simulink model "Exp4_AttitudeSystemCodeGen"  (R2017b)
settings: Solver=FixedStepDiscrete  StartTime=0.0  StopTime=inf  RelTol=1e-3
PreLoadFcn:
  | filepath  = fileparts(get_param(bdroot, 'FileName'))
  | cd(filepath);
InitFcn:
  | if exist('Init_control.m','file')
  |      Init_control;
  | end
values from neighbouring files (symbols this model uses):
  KiPitchAttitude = 0.0552303199591522 / kFactor    (= 0.0460252666326)    [Init_control.m]
  KiPitchRate = 0.460338699849681 / kFactor    (= 0.383615583208)    [Init_control.m]
  KiRollAttitude = 0.0552303199591522 / kFactor    (= 0.0460252666326)    [Init_control.m]
  KiRollRate = 0.460338699849681 / kFactor    (= 0.383615583208)    [Init_control.m]
  KiYawRate = 0.460338699849681 / kFactor * 2    (= 0.767231166416)    [Init_control.m]
  KpPitchAttitude = 0.630138625117681 / kFactor    (= 0.525115520931)    [Init_control.m]
  KpPitchRate = 1.31533836563383 / kFactor    (= 1.09611530469)    [Init_control.m]
  KpRollAttitude = 0.630138625117681 / kFactor    (= 0.525115520931)    [Init_control.m]
  KpRollRate = 1.31533836563383 / kFactor    (= 1.09611530469)    [Init_control.m]
  KpYawRate = 1.31533836563383 / kFactor * 2    (= 2.19223060939)    [Init_control.m]
undefined symbols (not defined in the file or in its folder): current_a, current_filtered_a, remaining, RGBLED_COLOR_ENUM, RGBLED_MODE_ENUM, voltage_filtered_v, voltage_v
libraries: simulink x6, pixhawk_slib_sensors_actuators x3, pixhawk_slib_uORB_RW x2

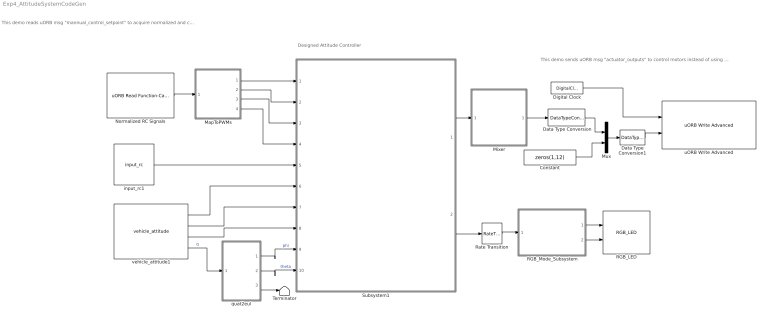
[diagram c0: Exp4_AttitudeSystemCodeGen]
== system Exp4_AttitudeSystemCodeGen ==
  note: Designed Attitude Controller
  note: This demo reads uORB msg "mannual_control_setpoint" to acquire normalized and calibrated RC signals (-1~1 for pitch, roll, yaw control, and 0~1 for throttle control) and then map them to 1000~2000's PWMs values. Compared with using the "input_rc" module to read RC PWM values directlly, this is more reliable and convinenient because you don't need to worry about calibration of RCs.
  note: This demo sends uORB msg "actuator_outputs" to control motors instead of using the "PWM_output" module, because this demo is for hardware-in-the-loop simulation, we need to send control signals to CopterSim instead of acutal motors.
  Constant : Constant  Value=zeros(1,12)
  Data Type Conversion : DataTypeConversion  OutDataTypeStr=double
  Data Type Conversion1 : DataTypeConversion  OutDataTypeStr=single
  Digital Clock : DigitalClock  SampleTime=-1
  MapToPWMs : Subsystem
  Mixer : Subsystem
  Mux : Mux  Inputs=2
  Normalized RC Signals : pixhawk_slib_uORB_RW/uORB Read Function-Call Trigger  uORB_Topic_str='manual_control_setpoint'  BusObjVar=Bus: manual_control_setpoint_SL  uORB_Interval=1  AsyncOutput=off  Fcn_call_select=Generate Function Call Signal  TaskName='Task1'  Poll_timeout=100  Ts=-1
  RGB_LED : pixhawk_slib_sensors_actuators/RGB_LED
  RGB_Mode_Subsystem : Subsystem
  Rate Transition : RateTransition  OutPortSampleTime=1
  Subsystem1 : Subsystem
  Terminator : Terminator
  input_rc1 : pixhawk_slib_sensors_actuators/input_rc  Description=|  sampletime=1/250  channel1=off  channel2=off  channel3=off  channel4=off  channel5=on  channel6=off  channel7=off  channel8=off  channel9=off  channel10=off  channel11=off  channel12=off  channel13=off  channel14=off  channel15=off  channel16=off  channel17=off  channel18=off  ch_count=off  rssi=off  rc_failsafe=off  rc_lost=off  rc_inputsource=off
      | RC Input Block
      | 
      | This block provides user input control to the model.
      | It uses the input_rc uORB topic.
      | 
      | The user has the ability to choose which channels are available as outputs from this block and also some optional outputs. These include 
      | Channels 1 through 18
      | double data type indicating the PWM value from the controller 
      | measured pulse widths for each of the supported channels 
      | Channel Count 
      | u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
  quat2eul : MATLAB Function  TreatAsAtomicUnit=on
  uORB Write Advanced : pixhawk_slib_uORB_RW/uORB Write Advanced  Ts=0  uORB_AdvtQueue=on  uORB_FieldEnabledArr="0  0  0  1  0  0  0  0  0  0  0"  uORB_Topic_str=0  uORB_Struct_DT="[1  1  1  1  1]"  BlockInputCount=5  uORB_StructParams="[\"voltage_v\",\"voltage_filtered_v\",\"current_a\",\"current_filtered_a\",\"remaining\"]"  uORB_PortSizes="[1  1  1  1]"  MsgSizeOf=0  MW_update=true
  vehicle_attitude1 : pixhawk_slib_sensors_actuators/vehicle_attitude  sampletime=1/250  show_r=on  show_p=on  show_y=on  show_q=on  show_ts=off
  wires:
  quat2eul/1(phi) -> Subsystem1/9(roll)  "phi"
  quat2eul/2(theta) -> Subsystem1/10(pitch)  "theta"
  vehicle_attitude1/1 -> Subsystem1/6(p)
  vehicle_attitude1/2 -> Subsystem1/7(q)
  vehicle_attitude1/3 -> Subsystem1/8(r)
  Digital Clock/1 -> uORB Write Advanced/1
  Mixer/1(pwms) -> Data Type Conversion/1
  Constant/1 -> Mux/2
  Mux/1 -> Data Type Conversion1/1
  Data Type Conversion/1 -> Mux/1
  RGB_Mode_Subsystem/1(RGB_MODE) -> RGB_LED/1
  Rate Transition/1 -> RGB_Mode_Subsystem/1(ARM_STATE)
  Subsystem1/2(ARM_Control) -> Rate Transition/1
  RGB_Mode_Subsystem/2(RGB_COLOR) -> RGB_LED/2
  vehicle_attitude1/4 -> quat2eul/1(q)  "q"
  quat2eul/3(psi) -> Terminator/1
  Data Type Conversion1/1 -> uORB Write Advanced/2
  input_rc1/1 -> Subsystem1/5(ch5)
  MapToPWMs/4(ch4) -> Subsystem1/4(ch4)
  MapToPWMs/3(ch3) -> Subsystem1/3(ch3)
  Normalized RC Signals/1 -> MapToPWMs/1(In1)
  MapToPWMs/1(ch1) -> Subsystem1/1(ch1)
  MapToPWMs/2(ch2) -> Subsystem1/2(ch2)
  Subsystem1/1(controls) -> Mixer/1(controls)

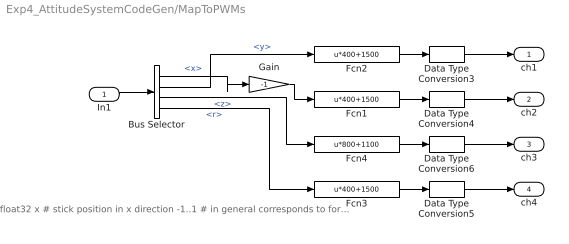
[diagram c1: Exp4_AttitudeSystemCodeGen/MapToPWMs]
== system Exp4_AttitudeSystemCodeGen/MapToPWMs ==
  note: float32 x # stick position in x direction -1..1 # in general corresponds to forward/back motion or pitch of vehicle, # in general a positive value means forward or negative pitch and # a negative value means backward or positive pitch float32 y # stick position in y direction -1..1 # in general corresponds to right/left motion or roll of vehicle, # in general a positive value means right or positive roll and # a negative value means left or negative roll float32 z # throttle stick position 0..1 # in general corresponds to up/down motion or thrust of vehicle, # in general the value corresponds to the demanded throttle by the user, # if the input is used for setting the setpoint of a vertical position # controller any value > 0.5 means up and any value < 0.5 means down float32 r # yaw stick/twist position, -1..1 # in general corresponds to the righthand rotation around the vertical # (downwards) axis of the vehicle
  In1 : Inport
  Bus Selector : BusSelector  OutputSignals=x,y,z,r
  Data Type Conversion{3..6} (4 alike) : DataTypeConversion  OutDataTypeStr=uint16
  Fcn1 : Fcn  Expr=u*400+1500
  Fcn2 : Fcn  Expr=u*400+1500
  Fcn3 : Fcn  Expr=u*400+1500
  Fcn4 : Fcn  Expr=u*800+1100
  Gain : Gain  Gain=-1
  ch1 : Outport
  ch2 : Outport  Port=2
  ch3 : Outport  Port=3
  ch4 : Outport  Port=4
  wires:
  Bus Selector/2 -> Fcn2/1  "<y>"
  Fcn2/1 -> Data Type Conversion3/1
  Bus Selector/1 -> Gain/1  "<x>"
  In1/1 -> Bus Selector/1
  Bus Selector/3 -> Fcn4/1  "<z>"
  Fcn1/1 -> Data Type Conversion4/1
  Bus Selector/4 -> Fcn3/1  "<r>"
  Data Type Conversion4/1 -> ch2/1
  Data Type Conversion5/1 -> ch4/1
  Data Type Conversion6/1 -> ch3/1
  Fcn4/1 -> Data Type Conversion6/1
  Fcn3/1 -> Data Type Conversion5/1
  Data Type Conversion3/1 -> ch1/1
  Gain/1 -> Fcn1/1

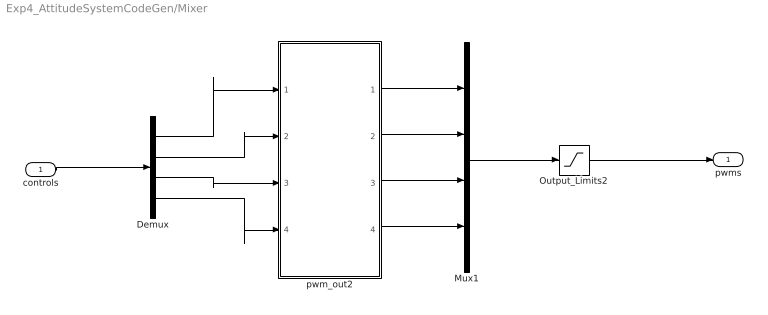
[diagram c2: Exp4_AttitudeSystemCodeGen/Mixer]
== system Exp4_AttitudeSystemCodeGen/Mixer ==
  controls : Inport
  Demux : Demux
  Mux1 : Mux
  Output_Limits2 : Saturate  UpperLimit=2000  LowerLimit=1000
  pwm_out2 : MATLAB Function  TreatAsAtomicUnit=on  SystemSampleTime=0.004
  pwms : Outport
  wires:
  controls/1 -> Demux/1
  Demux/4 -> pwm_out2/4(Thrust)
  Demux/3 -> pwm_out2/3(Yaw)
  Demux/1 -> pwm_out2/1(Roll)
  pwm_out2/1(M1) -> Mux1/1
  pwm_out2/2(M2) -> Mux1/2
  pwm_out2/3(M3) -> Mux1/3
  pwm_out2/4(M4) -> Mux1/4
  Mux1/1 -> Output_Limits2/1
  Demux/2 -> pwm_out2/2(Pitch)
  Output_Limits2/1 -> pwms/1

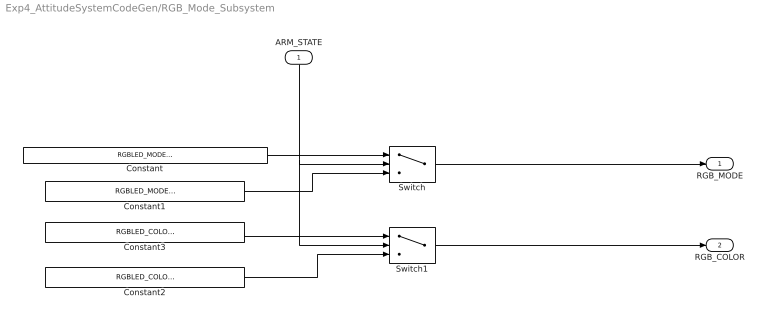
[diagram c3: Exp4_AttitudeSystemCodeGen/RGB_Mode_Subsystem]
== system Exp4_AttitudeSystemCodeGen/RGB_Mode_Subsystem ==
  ARM_STATE : Inport
  Constant : Constant  Value=RGBLED_MODE_ENUM.SL_MODE_BLINK_FAST  OutDataTypeStr=Enum: RGBLED_MODE_ENUM
  Constant1 : Constant  Value=RGBLED_MODE_ENUM.SL_MODE_BREATHE  OutDataTypeStr=Enum: RGBLED_MODE_ENUM
  Constant2 : Constant  Value=RGBLED_COLOR_ENUM.SL_COLOR_GREEN  OutDataTypeStr=Enum: RGBLED_COLOR_ENUM
  Constant3 : Constant  Value=RGBLED_COLOR_ENUM.SL_COLOR_RED  OutDataTypeStr=Enum: RGBLED_COLOR_ENUM
  Switch : Switch  Criteria=u2 ~= 0  Threshold=1500
  Switch1 : Switch  Criteria=u2 ~= 0  Threshold=1500
  RGB_MODE : Outport
  RGB_COLOR : Outport  Port=2
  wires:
  ARM_STATE/1 -> Switch1/2, Switch/2
  Constant/1 -> Switch/1
  Constant1/1 -> Switch/3
  Switch/1 -> RGB_MODE/1
  Constant3/1 -> Switch1/1
  Constant2/1 -> Switch1/3
  Switch1/1 -> RGB_COLOR/1

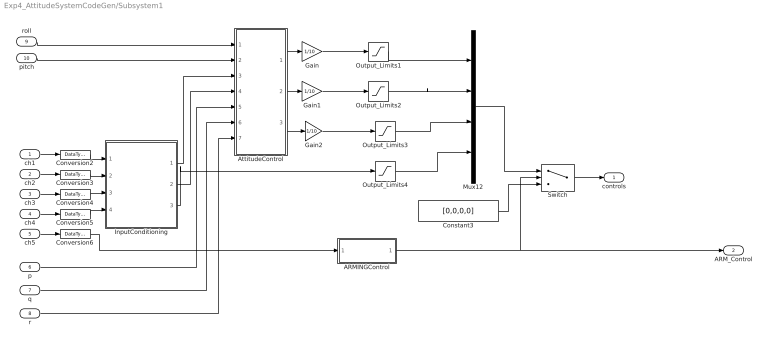
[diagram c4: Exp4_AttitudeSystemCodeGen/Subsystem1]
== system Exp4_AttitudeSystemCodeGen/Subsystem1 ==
  ch1 : Inport  OutDataTypeStr=uint16  PortDimensions=1
  ch2 : Inport  Port=2  OutDataTypeStr=uint16  PortDimensions=1
  ch3 : Inport  Port=3  OutDataTypeStr=uint16  PortDimensions=1
  ch4 : Inport  Port=4  OutDataTypeStr=uint16  PortDimensions=1
  ch5 : Inport  Port=5  OutDataTypeStr=uint16  PortDimensions=1  Interpolate=off
  p : Inport  Port=6  PortDimensions=1
  q : Inport  Port=7  PortDimensions=1
  r : Inport  Port=8  PortDimensions=1
  roll : Inport  Port=9  PortDimensions=1
  pitch : Inport  Port=10  PortDimensions=1
  ARMINGControl : Subsystem
  AttitudeControl : Subsystem
  Constant3 : Constant  Value=[0,0,0,0]
  Conversion{2..6} (5 alike) : DataTypeConversion  OutDataTypeStr=double
  Gain : Gain  Gain=1/10
  Gain1 : Gain  Gain=1/10
  Gain2 : Gain  Gain=1/10
  InputConditioning : Subsystem
  Mux12 : Mux
  Output_Limits1 : Saturate  UpperLimit=1  LowerLimit=-1
  Output_Limits2 : Saturate  UpperLimit=1  LowerLimit=-1
  Output_Limits3 : Saturate  UpperLimit=1  LowerLimit=-1
  Output_Limits4 : Saturate  UpperLimit=1  LowerLimit=0
  Switch : Switch  Criteria=u2 > Threshold  Threshold=0.5
  controls : Outport  PortDimensions=4
  ARM_Control : Outport  Port=2  PortDimensions=1
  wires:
  InputConditioning/3(Thrust) -> Output_Limits4/1
  q/1 -> AttitudeControl/6(q)
  ARMINGControl/1(Out1) -> Switch/2, ARM_Control/1
  Gain1/1 -> Output_Limits2/1
  pitch/1 -> AttitudeControl/2(theta)
  Gain/1 -> Output_Limits1/1
  Conversion5/1 -> InputConditioning/4(yaw)
  Output_Limits1/1 -> Mux12/1
  Gain2/1 -> Output_Limits3/1
  Output_Limits2/1 -> Mux12/2
  ch4/1 -> Conversion5/1
  r/1 -> AttitudeControl/7(r)
  AttitudeControl/3(Yaw) -> Gain2/1
  ch2/1 -> Conversion3/1
  ch5/1 -> Conversion6/1
  roll/1 -> AttitudeControl/1(phi)
  Conversion3/1 -> InputConditioning/2(pitch)
  Conversion4/1 -> InputConditioning/3(thrust)
  Conversion6/1 -> ARMINGControl/1(In1)
  Mux12/1 -> Switch/1
  Conversion2/1 -> InputConditioning/1(roll)
  AttitudeControl/2(Pitch) -> Gain1/1
  AttitudeControl/1(Roll) -> Gain/1
  ch1/1 -> Conversion2/1
  Output_Limits4/1 -> Mux12/4
  p/1 -> AttitudeControl/5(p)
  ch3/1 -> Conversion4/1
  InputConditioning/1(Roll_Pitch) -> AttitudeControl/3(roll_pitch_d)
  Output_Limits3/1 -> Mux12/3
  InputConditioning/2(Yaw) -> AttitudeControl/4(yaw_d)
  Switch/1 -> controls/1
  Constant3/1 -> Switch/3

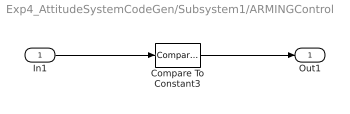
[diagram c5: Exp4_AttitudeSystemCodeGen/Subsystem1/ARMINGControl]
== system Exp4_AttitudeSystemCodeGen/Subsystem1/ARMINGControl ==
  In1 : Inport
  Compare To Constant3 : simulink/Logic and Bit Operations/Compare To Constant  relop=>=  const=uint16(1500)  OutDataTypeStr=boolean
  Out1 : Outport
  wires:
  Compare To Constant3/1 -> Out1/1
  In1/1 -> Compare To Constant3/1

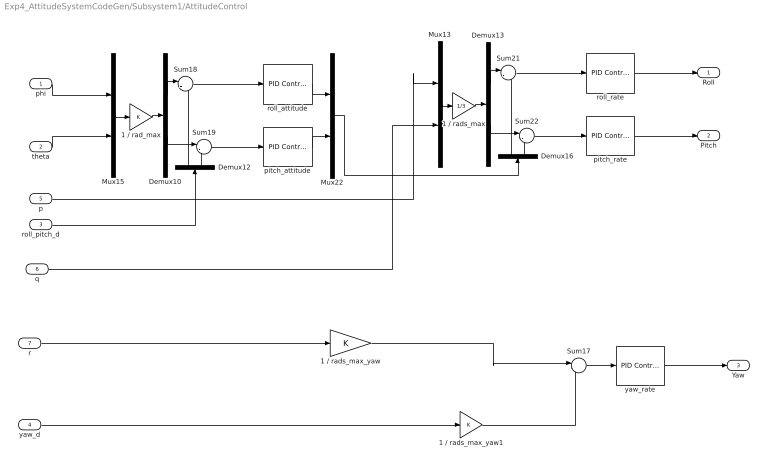
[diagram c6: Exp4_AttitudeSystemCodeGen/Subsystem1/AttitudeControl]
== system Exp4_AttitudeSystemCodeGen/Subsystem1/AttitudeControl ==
  phi : Inport
  theta : Inport  Port=2
  roll_pitch_d : Inport  Port=3
  yaw_d : Inport  Port=4
  p : Inport  Port=5
  q : Inport  Port=6
  r : Inport  Port=7
  1 / rad_max : Gain
  1 / rads_max : Gain  Gain=1/3
  1 / rads_max_yaw : Gain
  1 / rads_max_yaw1 : Gain
  Demux{10,12..13,16} (4 alike) : Demux  Outputs=2
  Mux13 : Mux  Inputs=2
  Mux15 : Mux  Inputs=2
  Mux22 : Mux  Inputs=2
  Sum{17..19,21..22} (5 alike) : Sum  Inputs=|-+
  pitch_attitude : simulink/Continuous/PID Controller  Controller=PI  TimeDomain=Discrete-time  SampleTime=-1  IntegratorMethod=Forward Euler  FilterMethod=Forward Euler  Form=Parallel  UseFilter=on  ControllerParametersSource=internal  P=KpPitchAttitude  I=KiPitchAttitude  D=0.01  N=100  InitialConditionSource=internal  InitialConditionForIntegrator=0  InitialConditionForFilter=0  ExternalReset=none  LimitOutput=on  UpperSaturationLimit=1  LowerSaturationLimit=-1  LinearizeAsGain=on  AntiWindupMode=back-calculation  Kb=1  TrackingMode=off  Kt=1  PParamMin=[]  PParamMax=[]  IParamMin=[]  IParamMax=[]  DParamMin=[]  DParamMax=[]  NParamMin=[]  NParamMax=[]  KbParamMin=[]  KbParamMax=[]  KtParamMin=[]  KtParamMax=[]  POutMin=[]  POutMax=[]  IOutMin=[]  IOutMax=[]  DOutMin=[]  DOutMax=[]  NOutMin=[]  NOutMax=[]  KbOutMin=[]  KbOutMax=[]  KtOutMin=[]  KtOutMax=[]  IntegratorOutMin=[]  IntegratorOutMax=[]  FilterOutMin=[]  FilterOutMax=[]  SumOutMin=[]  SumOutMax=[]  SumI1OutMin=[]  SumI1OutMax=[]  SumI2OutMin=[]  SumI2OutMax=[]  SumI3OutMin=[]  SumI3OutMax=[]  SumDOutMin=[]  SumDOutMax=[]  SaturationOutMin=[]  SaturationOutMax=[]  IntegratorContinuousStateAttributes=''  IntegratorStateMustResolveToSignalObject=off  IntegratorRTWStateStorageClass=Auto  FilterContinuousStateAttributes=''  FilterStateMustResolveToSignalObject=off  FilterRTWStateStorageClass=Auto  DifferentiatorICPrevScaledInput=0  DifferentiatorOutMin=[]  DifferentiatorOutMax=[]  InitialConditionSetting=State (most efficient)  FilterDiffOutCoefMin=[]  FilterDiffOutCoefMax=[]  SumDenOutMin=[]  SumDenOutMax=[]  SumNumOutMin=[]  SumNumOutMax=[]  ReciprocalOutMin=[]  ReciprocalOutMax=[]  DivideOutMin=[]  DivideOutMax=[]  TunerSelectOption=Transfer Function Based (PID Tuner App)
  pitch_rate : simulink/Continuous/PID Controller  Controller=PI  TimeDomain=Discrete-time  SampleTime=-1  IntegratorMethod=Forward Euler  FilterMethod=Forward Euler  Form=Parallel  UseFilter=on  ControllerParametersSource=internal  P=KpPitchRate  I=KiPitchRate  D=0.0024  N=100  InitialConditionSource=internal  InitialConditionForIntegrator=0  InitialConditionForFilter=0  ExternalReset=none  LimitOutput=on  UpperSaturationLimit=1  LowerSaturationLimit=-1  LinearizeAsGain=on  AntiWindupMode=back-calculation  Kb=1  TrackingMode=off  Kt=1  PParamMin=[]  PParamMax=[]  IParamMin=[]  IParamMax=[]  DParamMin=[]  DParamMax=[]  NParamMin=[]  NParamMax=[]  KbParamMin=[]  KbParamMax=[]  KtParamMin=[]  KtParamMax=[]  POutMin=[]  POutMax=[]  IOutMin=[]  IOutMax=[]  DOutMin=[]  DOutMax=[]  NOutMin=[]  NOutMax=[]  KbOutMin=[]  KbOutMax=[]  KtOutMin=[]  KtOutMax=[]  IntegratorOutMin=[]  IntegratorOutMax=[]  FilterOutMin=[]  FilterOutMax=[]  SumOutMin=[]  SumOutMax=[]  SumI1OutMin=[]  SumI1OutMax=[]  SumI2OutMin=[]  SumI2OutMax=[]  SumI3OutMin=[]  SumI3OutMax=[]  SumDOutMin=[]  SumDOutMax=[]  SaturationOutMin=[]  SaturationOutMax=[]  IntegratorContinuousStateAttributes=''  IntegratorStateMustResolveToSignalObject=off  IntegratorRTWStateStorageClass=Auto  FilterContinuousStateAttributes=''  FilterStateMustResolveToSignalObject=off  FilterRTWStateStorageClass=Auto  DifferentiatorICPrevScaledInput=0  DifferentiatorOutMin=[]  DifferentiatorOutMax=[]  InitialConditionSetting=State (most efficient)  FilterDiffOutCoefMin=[]  FilterDiffOutCoefMax=[]  SumDenOutMin=[]  SumDenOutMax=[]  SumNumOutMin=[]  SumNumOutMax=[]  ReciprocalOutMin=[]  ReciprocalOutMax=[]  DivideOutMin=[]  DivideOutMax=[]  TunerSelectOption=Transfer Function Based (PID Tuner App)
  roll_attitude : simulink/Continuous/PID Controller  Controller=PI  TimeDomain=Discrete-time  SampleTime=-1  IntegratorMethod=Forward Euler  FilterMethod=Forward Euler  Form=Parallel  UseFilter=on  ControllerParametersSource=internal  P=KpRollAttitude  I=KiRollAttitude  D=0.01  N=100  InitialConditionSource=internal  InitialConditionForIntegrator=0  InitialConditionForFilter=0  ExternalReset=none  LimitOutput=on  UpperSaturationLimit=1  LowerSaturationLimit=-1  LinearizeAsGain=on  AntiWindupMode=back-calculation  Kb=1  TrackingMode=off  Kt=1  PParamMin=[]  PParamMax=[]  IParamMin=[]  IParamMax=[]  DParamMin=[]  DParamMax=[]  NParamMin=[]  NParamMax=[]  KbParamMin=[]  KbParamMax=[]  KtParamMin=[]  KtParamMax=[]  POutMin=[]  POutMax=[]  IOutMin=[]  IOutMax=[]  DOutMin=[]  DOutMax=[]  NOutMin=[]  NOutMax=[]  KbOutMin=[]  KbOutMax=[]  KtOutMin=[]  KtOutMax=[]  IntegratorOutMin=[]  IntegratorOutMax=[]  FilterOutMin=[]  FilterOutMax=[]  SumOutMin=[]  SumOutMax=[]  SumI1OutMin=[]  SumI1OutMax=[]  SumI2OutMin=[]  SumI2OutMax=[]  SumI3OutMin=[]  SumI3OutMax=[]  SumDOutMin=[]  SumDOutMax=[]  SaturationOutMin=[]  SaturationOutMax=[]  IntegratorContinuousStateAttributes=''  IntegratorStateMustResolveToSignalObject=off  IntegratorRTWStateStorageClass=Auto  FilterContinuousStateAttributes=''  FilterStateMustResolveToSignalObject=off  FilterRTWStateStorageClass=Auto  DifferentiatorICPrevScaledInput=0  DifferentiatorOutMin=[]  DifferentiatorOutMax=[]  InitialConditionSetting=State (most efficient)  FilterDiffOutCoefMin=[]  FilterDiffOutCoefMax=[]  SumDenOutMin=[]  SumDenOutMax=[]  SumNumOutMin=[]  SumNumOutMax=[]  ReciprocalOutMin=[]  ReciprocalOutMax=[]  DivideOutMin=[]  DivideOutMax=[]  TunerSelectOption=Transfer Function Based (PID Tuner App)
  roll_rate : simulink/Continuous/PID Controller  Controller=PI  TimeDomain=Discrete-time  SampleTime=-1  IntegratorMethod=Forward Euler  FilterMethod=Forward Euler  Form=Parallel  UseFilter=on  ControllerParametersSource=internal  P=KpRollRate  I=KiRollRate  D=0.0024  N=100  InitialConditionSource=internal  InitialConditionForIntegrator=0  InitialConditionForFilter=0  ExternalReset=none  LimitOutput=on  UpperSaturationLimit=1  LowerSaturationLimit=-1  LinearizeAsGain=on  AntiWindupMode=back-calculation  Kb=1  TrackingMode=off  Kt=1  PParamMin=[]  PParamMax=[]  IParamMin=[]  IParamMax=[]  DParamMin=[]  DParamMax=[]  NParamMin=[]  NParamMax=[]  KbParamMin=[]  KbParamMax=[]  KtParamMin=[]  KtParamMax=[]  POutMin=[]  POutMax=[]  IOutMin=[]  IOutMax=[]  DOutMin=[]  DOutMax=[]  NOutMin=[]  NOutMax=[]  KbOutMin=[]  KbOutMax=[]  KtOutMin=[]  KtOutMax=[]  IntegratorOutMin=[]  IntegratorOutMax=[]  FilterOutMin=[]  FilterOutMax=[]  SumOutMin=[]  SumOutMax=[]  SumI1OutMin=[]  SumI1OutMax=[]  SumI2OutMin=[]  SumI2OutMax=[]  SumI3OutMin=[]  SumI3OutMax=[]  SumDOutMin=[]  SumDOutMax=[]  SaturationOutMin=[]  SaturationOutMax=[]  IntegratorContinuousStateAttributes=''  IntegratorStateMustResolveToSignalObject=off  IntegratorRTWStateStorageClass=Auto  FilterContinuousStateAttributes=''  FilterStateMustResolveToSignalObject=off  FilterRTWStateStorageClass=Auto  DifferentiatorICPrevScaledInput=0  DifferentiatorOutMin=[]  DifferentiatorOutMax=[]  InitialConditionSetting=State (most efficient)  FilterDiffOutCoefMin=[]  FilterDiffOutCoefMax=[]  SumDenOutMin=[]  SumDenOutMax=[]  SumNumOutMin=[]  SumNumOutMax=[]  ReciprocalOutMin=[]  ReciprocalOutMax=[]  DivideOutMin=[]  DivideOutMax=[]  TunerSelectOption=Transfer Function Based (PID Tuner App)
  yaw_rate : simulink/Continuous/PID Controller  Controller=PI  TimeDomain=Discrete-time  SampleTime=-1  IntegratorMethod=Forward Euler  FilterMethod=Forward Euler  Form=Parallel  UseFilter=on  ControllerParametersSource=internal  P=KpYawRate  I=KiYawRate  D=0  N=100  InitialConditionSource=internal  InitialConditionForIntegrator=0  InitialConditionForFilter=0  ExternalReset=none  LimitOutput=on  UpperSaturationLimit=1  LowerSaturationLimit=-1  LinearizeAsGain=on  AntiWindupMode=back-calculation  Kb=1  TrackingMode=off  Kt=1  PParamMin=[]  PParamMax=[]  IParamMin=[]  IParamMax=[]  DParamMin=[]  DParamMax=[]  NParamMin=[]  NParamMax=[]  KbParamMin=[]  KbParamMax=[]  KtParamMin=[]  KtParamMax=[]  POutMin=[]  POutMax=[]  IOutMin=[]  IOutMax=[]  DOutMin=[]  DOutMax=[]  NOutMin=[]  NOutMax=[]  KbOutMin=[]  KbOutMax=[]  KtOutMin=[]  KtOutMax=[]  IntegratorOutMin=[]  IntegratorOutMax=[]  FilterOutMin=[]  FilterOutMax=[]  SumOutMin=[]  SumOutMax=[]  SumI1OutMin=[]  SumI1OutMax=[]  SumI2OutMin=[]  SumI2OutMax=[]  SumI3OutMin=[]  SumI3OutMax=[]  SumDOutMin=[]  SumDOutMax=[]  SaturationOutMin=[]  SaturationOutMax=[]  IntegratorContinuousStateAttributes=''  IntegratorStateMustResolveToSignalObject=off  IntegratorRTWStateStorageClass=Auto  FilterContinuousStateAttributes=''  FilterStateMustResolveToSignalObject=off  FilterRTWStateStorageClass=Auto  DifferentiatorICPrevScaledInput=0  DifferentiatorOutMin=[]  DifferentiatorOutMax=[]  InitialConditionSetting=State (most efficient)  FilterDiffOutCoefMin=[]  FilterDiffOutCoefMax=[]  SumDenOutMin=[]  SumDenOutMax=[]  SumNumOutMin=[]  SumNumOutMax=[]  ReciprocalOutMin=[]  ReciprocalOutMax=[]  DivideOutMin=[]  DivideOutMax=[]  TunerSelectOption=Transfer Function Based (PID Tuner App)
  Roll : Outport
  Pitch : Outport  Port=2
  Yaw : Outport  Port=3
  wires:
  r/1 -> 1 / rads_max_yaw/1
  q/1 -> Mux13/2
  Mux22/1 -> Demux16/1
  yaw_rate/1 -> Yaw/1
  phi/1 -> Mux15/1
  Mux15/1 -> 1 / rad_max/1
  theta/1 -> Mux15/2
  1 / rads_max_yaw/1 -> Sum17/1
  roll_rate/1 -> Roll/1
  Sum19/1 -> pitch_attitude/1
  pitch_attitude/1 -> Mux22/2
  roll_attitude/1 -> Mux22/1
  Demux16/1 -> Sum21/2
  yaw_d/1 -> 1 / rads_max_yaw1/1
  roll_pitch_d/1 -> Demux12/1
  Demux16/2 -> Sum22/2
  Demux12/1 -> Sum18/2
  Demux12/2 -> Sum19/2
  p/1 -> Mux13/1
  Demux10/1 -> Sum18/1
  Demux10/2 -> Sum19/1
  1 / rad_max/1 -> Demux10/1
  Sum18/1 -> roll_attitude/1
  pitch_rate/1 -> Pitch/1
  Mux13/1 -> 1 / rads_max/1
  Sum22/1 -> pitch_rate/1
  Sum17/1 -> yaw_rate/1
  Demux13/1 -> Sum21/1
  Demux13/2 -> Sum22/1
  1 / rads_max/1 -> Demux13/1
  Sum21/1 -> roll_rate/1
  1 / rads_max_yaw1/1 -> Sum17/2

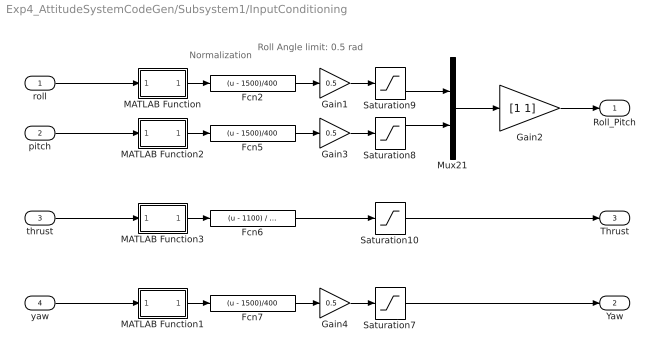
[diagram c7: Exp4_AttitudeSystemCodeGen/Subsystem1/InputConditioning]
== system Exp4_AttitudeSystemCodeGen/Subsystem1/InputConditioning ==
  note: Roll Angle limit: 0.5 rad
  note: Normalization
  roll : Inport
  pitch : Inport  Port=2
  thrust : Inport  Port=3
  yaw : Inport  Port=4
  Fcn2 : Fcn  Expr=(u - 1500)/400
  Fcn5 : Fcn  Expr=(u - 1500)/400
  Fcn6 : Fcn  Expr=(u - 1100) / 800
  Fcn7 : Fcn  Expr=(u - 1500)/400
  Gain1 : Gain  Gain=0.5
  Gain2 : Gain  Gain=[1 1]  OutDataTypeStr=Inherit: Inherit via back propagation
  Gain3 : Gain  Gain=0.5
  Gain4 : Gain  Gain=0.5
  MATLAB Function : MATLAB Function  TreatAsAtomicUnit=on
  MATLAB Function1 : MATLAB Function  TreatAsAtomicUnit=on
  MATLAB Function2 : MATLAB Function  TreatAsAtomicUnit=on
  MATLAB Function3 : MATLAB Function  TreatAsAtomicUnit=on
  Mux21 : Mux  Inputs=2
  Saturation10 : Saturate  UpperLimit=1  LowerLimit=0
  Saturation7 : Saturate  UpperLimit=1  LowerLimit=-1
  Saturation8 : Saturate  UpperLimit=1  LowerLimit=-1
  Saturation9 : Saturate  UpperLimit=1  LowerLimit=-1
  Roll_Pitch : Outport
  Yaw : Outport  Port=2
  Thrust : Outport  Port=3
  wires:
  Saturation10/1 -> Thrust/1
  Gain2/1 -> Roll_Pitch/1
  Mux21/1 -> Gain2/1
  Saturation8/1 -> Mux21/2
  Fcn6/1 -> Saturation10/1
  Fcn2/1 -> Gain1/1
  Fcn5/1 -> Gain3/1
  Saturation9/1 -> Mux21/1
  Fcn7/1 -> Gain4/1
  pitch/1 -> MATLAB Function2/1(u)
  MATLAB Function1/1(y) -> Fcn7/1
  thrust/1 -> MATLAB Function3/1(u)
  roll/1 -> MATLAB Function/1(u)
  MATLAB Function2/1(y) -> Fcn5/1
  MATLAB Function/1(y) -> Fcn2/1
  yaw/1 -> MATLAB Function1/1(u)
  MATLAB Function3/1(y) -> Fcn6/1
  Saturation7/1 -> Yaw/1
  Gain1/1 -> Saturation9/1
  Gain3/1 -> Saturation8/1
  Gain4/1 -> Saturation7/1

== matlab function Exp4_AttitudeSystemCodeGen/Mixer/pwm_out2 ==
function [M1, M2, M3, M4] = motor_mixer(Roll, Pitch, Yaw, Thrust)

idle_PWM = 1000;

% Quad XROLL （根据QP里面的叉字形结构的文字）
% M1 = ((Pitch+ Yaw)+Thrust-Roll) * 1000 + idle_PWM;
 %M2 = ((Pitch - Yaw)+Thrust+Roll) * 1000 + idle_PWM;
 %M3 = ((Roll +Yaw) + Thrust-Pitch) * 1000 + idle_PWM;
 %M4 = ((-Roll - Pitch-Yaw) + Thrust) * 1000 + idle_PWM;
% M5 = 1000;
% M6 = 1000;
% M7 = 1000;
% M8 = 1000;
%qp上实际的输出
M1 = (Thrust+Pitch-Roll+Yaw) * 1000 + idle_PWM;
 M2 = (Thrust-Pitch +Roll+Yaw) * 1000 + idle_PWM;
 M3 = ( Thrust+Roll+Pitch-Yaw) * 1000 + idle_PWM;
 M4 = (Thrust-Roll- Pitch -Yaw) * 1000 + idle_PWM;
% Quad +
 %M1 = ((Pitch - Yaw) * Thrust / 2 + Thrust) * 1000 + idle_PWM;
 %M2 = ((-Roll + Yaw) * Thrust / 2 + Thrust) * 1000 + idle_PWM;
% M3 = ((-Pitch - Yaw) * Thrust / 2 + Thrust) * 1000 + idle_PWM;
 %M4 = ((Roll + Yaw) * Thrust / 2 + Thrust) * 1000 + idle_PWM;
% M5 = 1000;
% M6 = 1000;
% M7 = 1000;
% M8 = 1000;

% Hex X
% M1 = ((Pitch + Roll / 2 - Yaw) * Thrust / 2 + Thrust) * 1000 + idle_PWM;
% M2 = ((Pitch - Roll / 2 + Yaw) * Thrust / 2 + Thrust) * 1000 + idle_PWM;
% M3 = ((-Roll - Yaw) * Thrust / 2 + Thrust) * 1000 + idle_PWM;
% M4 = ((-Pitch - Roll / 2 + Yaw) * Thrust / 2 + Thrust) * 1000 + idle_PWM;
% M5 = ((-Pitch + Roll / 2 - Yaw) * Thrust / 2 + Thrust) * 1000 + idle_PWM;
% M6 = ((Roll + Yaw) * Thrust / 2 + Thrust) * 1000 + idle_PWM;
% M7 = 1000;
% M8 = 1000;

% Hex X (From Adam)
%M1 = uint16(single(((-Roll - Yaw) * Thrust / 3 + Thrust) * single(1000))) + idle_PWM;
%M2 = uint16(single(((Roll + Yaw) * Thrust / 3 + Thrust) * single(1000))) + idle_PWM;
%M3 = uint16(single(((Pitch + (Roll / 2) - Yaw) * Thrust / 3 + Thrust) * single(1000))) + idle_PWM;
%M4 = uint16(single(((-Pitch - (Roll / 2) + Yaw) * Thrust / 3 + Thrust) * single(1000))) + idle_PWM;
%M5 = uint16(single(((Pitch - (Roll / 2) + Yaw) * Thrust / 3 + Thrust) * single(1000))) + idle_PWM;
%M6 = uint16(single(((-Pitch + (Roll / 2) - Yaw) * Thrust / 3 + Thrust) * single(1000))) + idle_PWM;

% Hex X (Version 2)
% Roll/Yaw
% M1 = ((-Roll - Yaw) * Thrust / 2 + Thrust) * 1000 + idle_PWM;
% M2 = ((Roll + Yaw) * Thrust / 2 + Thrust) * 1000 + idle_PWM;
% % + Pitch/Roll
% M6 = ((Pitch + Roll / 2 - Yaw) * Thrust / 2 + Thrust) * 1000 + idle_PWM;
% M4 = ((Pitch - Roll / 2 + Yaw) * Thrust / 2 + Thrust) * 1000 + idle_PWM;
% % - Pitch/Roll
% M5 = ((-Pitch - Roll / 2 + Yaw) * Thrust / 2 + Thrust) * 1000 + idle_PWM;
% M3 = ((-Pitch + Roll / 2 - Yaw) * Thrust / 2 + Thrust) * 1000 + idle_PWM;

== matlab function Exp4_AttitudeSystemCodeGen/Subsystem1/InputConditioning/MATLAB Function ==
function y = fcn(u)
%将遥控输入的范围控制在1100~1900，同时设置一个死区，死区大小为±deadZone
RCMin = 1100;
RCMax = 1900;
deadZoneRate = 0.05;
deadZone = deadZoneRate*(RCMax-RCMin);
%限幅
if(u < RCMin)
    u = RCMin;
elseif(u > RCMax)
    u = RCMax;
end
%死区
 if(u > 1500+deadZone)
    y = u;
 elseif(u < 1500-deadZone)
     y = u;
 else
     y = 1500;
 end
     
 end

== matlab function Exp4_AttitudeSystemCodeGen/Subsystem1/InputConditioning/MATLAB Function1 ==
function y = fcn(u)
%将遥控输入的范围控制在1100~1900，同时设置一个死区，死区大小为±deadZone
RCMin = 1100;
RCMax = 1900;
deadZoneRate = 0.05;
deadZone = deadZoneRate*(RCMax-RCMin);
%限幅
if(u < RCMin)
    u = RCMin;
elseif(u > RCMax)
    u = RCMax;
end
%死区
 if(u > 1500+deadZone)
    y = u;
 elseif(u < 1500-deadZone)
     y = u;
 else
     y = 1500;
 end
     
 end

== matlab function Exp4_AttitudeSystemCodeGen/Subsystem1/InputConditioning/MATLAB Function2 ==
function y = fcn(u)
%将遥控输入的范围控制在1100~1900，同时设置一个死区，死区大小为±deadZone
RCMin = 1100;
RCMax = 1900;
deadZoneRate = 0.05;
deadZone = deadZoneRate*(RCMax-RCMin);
%限幅
if(u < RCMin)
    u = RCMin;
elseif(u > RCMax)
    u = RCMax;
end
%死区
 if(u > 1500+deadZone)
    y = u;
 elseif(u < 1500-deadZone)
     y = u;
 else
     y = 1500;
 end
     
 end

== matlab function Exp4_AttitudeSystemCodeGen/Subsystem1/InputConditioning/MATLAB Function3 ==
function y = fcn(u)
%将遥控输入的范围控制在1100~1900，同时设置一个死区，死区大小为±deadZone
RCMin = 1100;
RCMax = 1900;
deadZoneRate = 0.05;
deadZone = deadZoneRate*(RCMax-RCMin);
%限幅
if(u < RCMin)
    u = RCMin;
elseif(u > RCMax)
    u = RCMax;
end
%死区
 if(u > 1500+deadZone)
    y = u;
 elseif(u < 1500-deadZone)
     y = u;
 else
     y = 1500;
 end
     
 end

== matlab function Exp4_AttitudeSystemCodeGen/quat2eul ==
function [phi,theta,psi] = quat2eul(q)
% Conversion from Quaternion to Euler angles based on the PX4 Firmware
% v1.6.5 release.
% 
% Quaternion -> DCM -> Euler Angles
% INPUT:
%   q: Quaternion vector of the format: (a + bi + cj + dk)
% OUTPUT:
%   [phi,theta,psi]: Euler angles in radians.
% 
 
    a = q(1);
    b = q(2);
    c = q(3);
    d = q(4);

    aSq = a*a;
    bSq = b*b;
    cSq = c*c;
    dSq = d*d;

    d_pi2 = pi/2;

    % quaternion_to_dcm
    dcm00 = aSq + bSq - cSq - dSq;
    % dcm01 = 2*(b*c - a*d);
    dcm02 = 2*(a*c + b*d);
    dcm10 = 2*(b*c + a*d);
    % dcm11 = aSq - bSq + cSq - dSq;
    dcm12 = 2*(c*d - a*b);
    dcm20 = 2*(b*d - a*c);
    dcm21 = 2*(a*b + c*d);
    dcm22 = aSq - bSq - cSq + dSq;

    % dcm_to_euler
    theta = asin(-dcm20);
    if abs(theta - d_pi2) < 1.0e-3
        phi = single(0.0);
        psi = atan2(dcm12, dcm02);
    elseif abs(theta + d_pi2) < 1.0e-3
        phi = single(0.0);
        psi = atan2(-dcm12, -dcm02);
    else
        phi = atan2(dcm21, dcm22);
        psi = atan2(dcm10, dcm00);
    end

end
